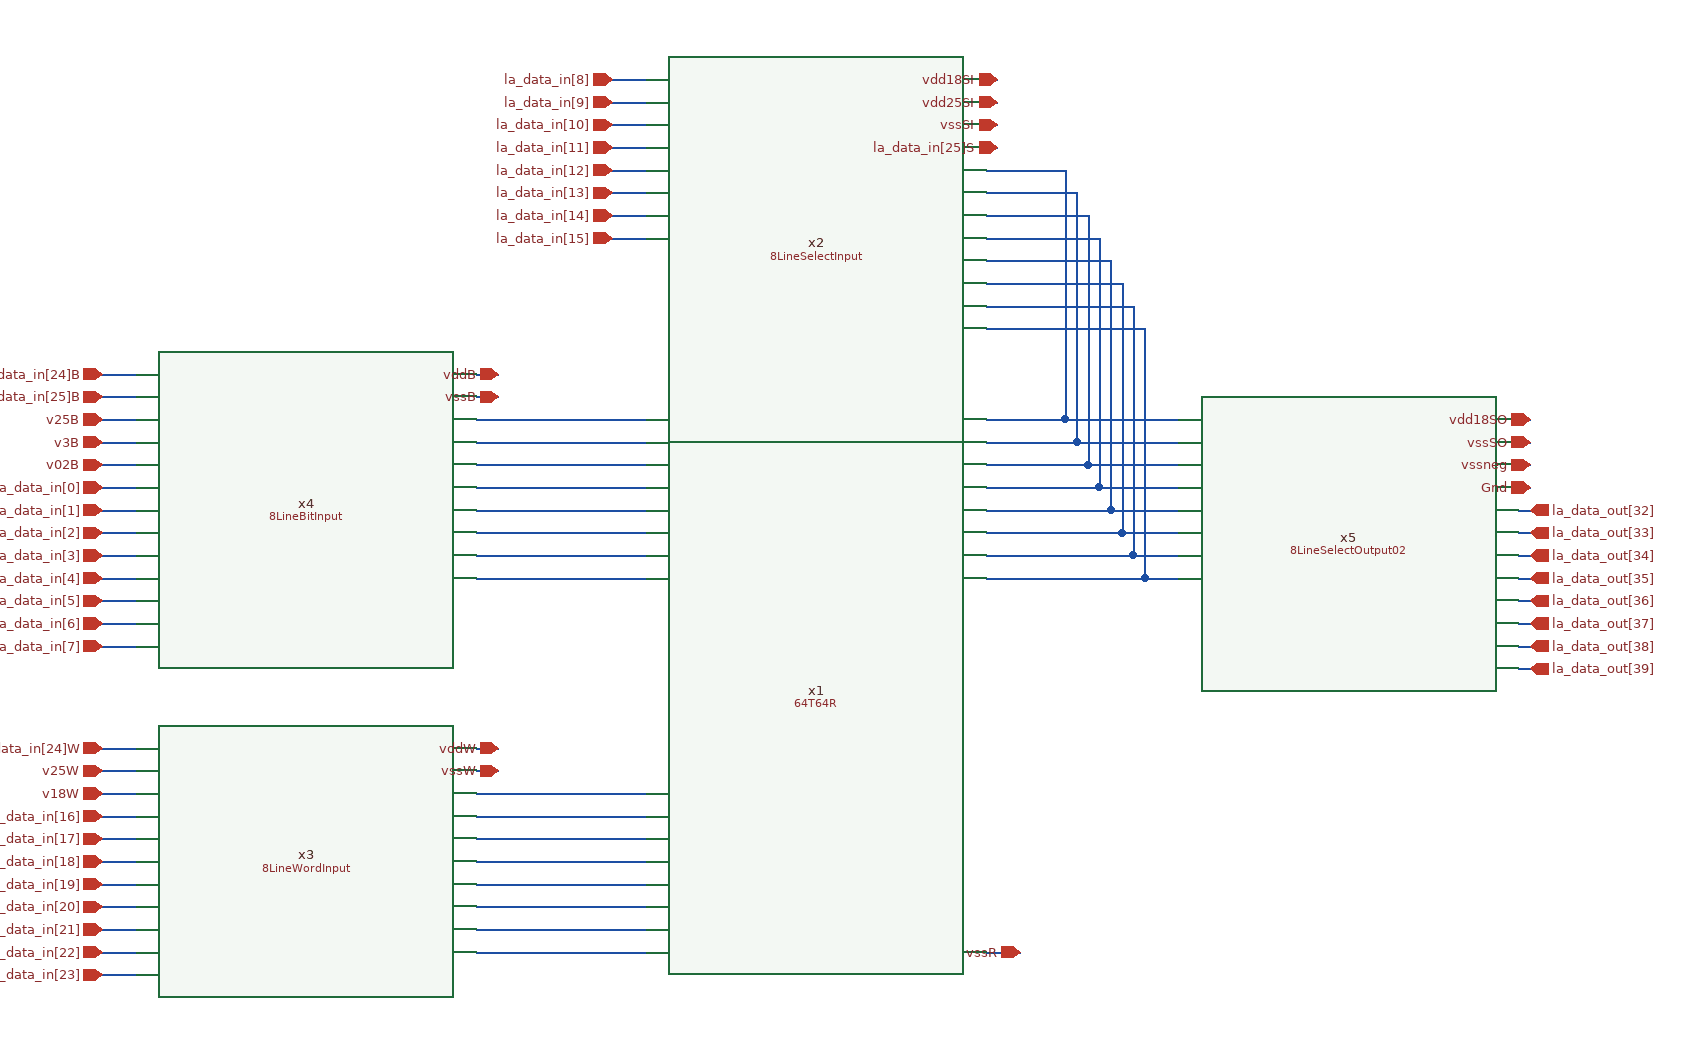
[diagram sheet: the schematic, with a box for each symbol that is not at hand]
v {xschem version=3.4.4 file_version=1.2
}
G {}
K {}
V {}
S {}
E {}
N 1830 1180 1860 1180 {
lab=vssR}
N 1830 450 1840 450 {
lab=vssSI}
N 1830 410 1840 410 {
lab=vdd18SI}
N 1830 490 1900 490 {
lab=#net1}
N 1830 710 1900 710 {
lab=#net1}
N 1830 730 1910 730 {
lab=#net2}
N 1830 510 1910 510 {
lab=#net2}
N 1830 530 1920 530 {
lab=#net3}
N 1830 750 1920 750 {
lab=#net3}
N 1830 550 1930 550 {
lab=#net4}
N 1830 770 1930 770 {
lab=#net4}
N 1830 570 1940 570 {
lab=#net5}
N 1830 790 1940 790 {
lab=#net5}
N 1830 590 1950 590 {
lab=#net6}
N 1830 810 1950 810 {
lab=#net6}
N 1830 830 1960 830 {
lab=#net7}
N 1830 610 1960 610 {
lab=#net7}
N 1830 630 1970 630 {
lab=#net8}
N 1830 850 1970 850 {
lab=#net8}
N 1500 410 1530 410 {
lab=la_data_in[8]}
N 1500 430 1530 430 {
lab=la_data_in[9]}
N 1500 450 1530 450 {
lab=la_data_in[10]}
N 1500 470 1530 470 {
lab=la_data_in[11]}
N 1500 490 1530 490 {
lab=la_data_in[12]}
N 1500 510 1530 510 {
lab=la_data_in[13]}
N 1500 530 1530 530 {
lab=la_data_in[14]}
N 1500 550 1530 550 {
lab=la_data_in[15]}
N 1380 1040 1530 1040 {
lab=#net9}
N 1380 1060 1530 1060 {
lab=#net10}
N 1380 1080 1530 1080 {
lab=#net11}
N 1380 1100 1530 1100 {
lab=#net12}
N 1380 1120 1530 1120 {
lab=#net13}
N 1380 1140 1530 1140 {
lab=#net14}
N 1380 1160 1530 1160 {
lab=#net15}
N 1380 1180 1530 1180 {
lab=#net16}
N 1380 1020 1400 1020 {
lab=vssW}
N 1050 1060 1080 1060 {
lab=la_data_in[16]}
N 1050 1080 1080 1080 {
lab=la_data_in[17]}
N 1050 1100 1080 1100 {
lab=la_data_in[18]}
N 1050 1120 1080 1120 {
lab=la_data_in[19]}
N 1050 1140 1080 1140 {
lab=la_data_in[20]}
N 1050 1160 1080 1160 {
lab=la_data_in[21]}
N 1050 1180 1080 1180 {
lab=la_data_in[22]}
N 1050 1200 1080 1200 {
lab=la_data_in[23]}
N 1380 710 1530 710 {
lab=#net17}
N 1380 730 1530 730 {
lab=#net18}
N 1380 750 1530 750 {
lab=#net19}
N 1380 770 1530 770 {
lab=#net20}
N 1380 790 1530 790 {
lab=#net21}
N 1380 810 1530 810 {
lab=#net22}
N 1380 830 1530 830 {
lab=#net23}
N 1380 850 1530 850 {
lab=#net24}
N 1380 690 1400 690 {
lab=vssB}
N 1380 670 1400 670 {
lab=vddB}
N 1380 1000 1400 1000 {
lab=vddW}
N 1050 910 1080 910 {
lab=la_data_in[7]}
N 1050 890 1080 890 {
lab=la_data_in[6]}
N 1050 870 1080 870 {
lab=la_data_in[5]}
N 1050 850 1080 850 {
lab=la_data_in[4]}
N 1050 830 1080 830 {
lab=la_data_in[3]}
N 1050 810 1080 810 {
lab=la_data_in[2]}
N 1050 790 1080 790 {
lab=la_data_in[1]}
N 1050 770 1080 770 {
lab=la_data_in[0]}
N 1050 750 1080 750 {
lab=v02B}
N 1050 730 1080 730 {
lab=v3B}
N 1050 710 1080 710 {
lab=v25B}
N 1050 1040 1080 1040 {
lab=v18W}
N 1050 1020 1080 1020 {
lab=v25W}
N 1050 1000 1080 1000 {
lab=la_data_in[24]W}
N 1050 690 1080 690 {
lab=la_data_in[25]B}
N 1050 670 1080 670 {
lab=la_data_in[24]B}
N 1830 470 1840 470 {
lab=la_data_in[25]S}
N 1830 430 1840 430 {
lab=vdd25SI}
N 1900 490 1900 710 {
lab=#net1}
N 1910 510 1910 730 {
lab=#net2}
N 1920 530 1920 750 {
lab=#net3}
N 1930 550 1930 770 {
lab=#net4}
N 1940 570 1940 790 {
lab=#net5}
N 1950 590 1950 810 {
lab=#net6}
N 1960 610 1960 830 {
lab=#net7}
N 1970 630 1970 850 {
lab=#net8}
N 1970 850 2000 850 {
lab=#net8}
N 1960 830 2000 830 {
lab=#net7}
N 1950 810 2000 810 {
lab=#net6}
N 1940 790 2000 790 {
lab=#net5}
N 1930 770 2000 770 {
lab=#net4}
N 1920 750 2000 750 {
lab=#net3}
N 1910 730 2000 730 {
lab=#net2}
N 1900 710 2000 710 {
lab=#net1}
N 2300 710 2310 710 {
lab=vdd18SO}
N 2300 730 2310 730 {
lab=vssSO}
N 2300 750 2310 750 {
lab=vssneg}
N 2300 770 2310 770 {
lab=Gnd}
N 2300 790 2310 790 {
lab=la_data_out[32]}
N 2300 810 2310 810 {
lab=la_data_out[33]}
N 2300 830 2310 830 {
lab=la_data_out[34]}
N 2300 850 2310 850 {
lab=la_data_out[35]}
N 2300 870 2310 870 {
lab=la_data_out[36]}
N 2300 890 2310 890 {
lab=la_data_out[37]}
N 2300 910 2310 910 {
lab=la_data_out[38]}
N 2300 930 2310 930 {
lab=la_data_out[32]}
C {64T64R.sym} 1680 940 0 0 {name=x1}
C {8LineSelectInput.sym} 1680 520 0 0 {name=x2}
C {8LineWordInput.sym} 1230 1100 0 0 {name=x3}
C {8LineBitInput.sym} 1230 790 0 0 {name=x4}
C {devices/ipin.sym} 1500 410 0 0 {name=p1 lab=la_data_in[8]}
C {devices/ipin.sym} 1500 550 0 0 {name=p2 lab=la_data_in[15]}
C {devices/ipin.sym} 1500 430 0 0 {name=p3 lab=la_data_in[9]}
C {devices/ipin.sym} 1500 450 0 0 {name=p4 lab=la_data_in[10]}
C {devices/ipin.sym} 1500 530 0 0 {name=p5 lab=la_data_in[14]}
C {devices/ipin.sym} 1500 510 0 0 {name=p6 lab=la_data_in[13]}
C {devices/ipin.sym} 1500 490 0 0 {name=p7 lab=la_data_in[12]}
C {devices/ipin.sym} 1500 470 0 0 {name=p8 lab=la_data_in[11]}
C {devices/ipin.sym} 1050 770 0 0 {name=p9 lab=la_data_in[0]}
C {devices/ipin.sym} 1050 790 0 0 {name=p10 lab=la_data_in[1]}
C {devices/ipin.sym} 1050 810 0 0 {name=p11 lab=la_data_in[2]}
C {devices/ipin.sym} 1050 830 0 0 {name=p12 lab=la_data_in[3]}
C {devices/ipin.sym} 1050 850 0 0 {name=p13 lab=la_data_in[4]}
C {devices/ipin.sym} 1050 870 0 0 {name=p14 lab=la_data_in[5]}
C {devices/ipin.sym} 1050 890 0 0 {name=p15 lab=la_data_in[6]}
C {devices/ipin.sym} 1050 910 0 0 {name=p16 lab=la_data_in[7]}
C {devices/ipin.sym} 1050 1060 0 0 {name=p17 lab=la_data_in[16]}
C {devices/ipin.sym} 1050 1080 0 0 {name=p18 lab=la_data_in[17]}
C {devices/ipin.sym} 1050 1100 0 0 {name=p19 lab=la_data_in[18]}
C {devices/ipin.sym} 1050 1120 0 0 {name=p20 lab=la_data_in[19]}
C {devices/ipin.sym} 1050 1140 0 0 {name=p21 lab=la_data_in[20]}
C {devices/ipin.sym} 1050 1160 0 0 {name=p22 lab=la_data_in[21]}
C {devices/ipin.sym} 1050 1180 0 0 {name=p23 lab=la_data_in[22]}
C {devices/ipin.sym} 1050 1200 0 0 {name=p24 lab=la_data_in[23]}
C {devices/ipin.sym} 1050 670 0 0 {name=p25 lab=la_data_in[24]B}
C {devices/ipin.sym} 1050 1000 0 0 {name=p26 lab=la_data_in[24]W}
C {devices/ipin.sym} 1050 690 0 0 {name=p27 lab=la_data_in[25]B}
C {devices/ipin.sym} 1840 470 2 0 {name=p28 lab=la_data_in[25]S}
C {devices/ipin.sym} 1050 710 0 0 {name=p29 lab=v25B}
C {devices/ipin.sym} 1050 730 0 0 {name=p30 lab=v3B}
C {devices/ipin.sym} 1050 750 0 0 {name=p31 lab=v02B}
C {devices/ipin.sym} 1050 1020 0 0 {name=p32 lab=v25W}
C {devices/ipin.sym} 1050 1040 0 0 {name=p33 lab=v18W}
C {devices/iopin.sym} 1400 670 0 0 {name=p34 lab=vddB}
C {devices/iopin.sym} 1400 690 0 0 {name=p35 lab=vssB}
C {devices/iopin.sym} 1400 1020 0 0 {name=p36 lab=vssW}
C {devices/iopin.sym} 1400 1000 0 0 {name=p37 lab=vddW}
C {devices/iopin.sym} 1860 1180 0 0 {name=p38 lab=vssR}
C {devices/iopin.sym} 1840 410 0 0 {name=p39 lab=vdd18SI}
C {devices/iopin.sym} 1840 430 0 0 {name=p40 lab=vdd25SI}
C {devices/iopin.sym} 1840 450 0 0 {name=p41 lab=vssSI}
C {8LineSelectOutput02.sym} 2150 820 0 0 {name=x5}
C {devices/iopin.sym} 2310 710 0 0 {name=p42 lab=vdd18SO}
C {devices/iopin.sym} 2310 730 0 0 {name=p43 lab=vssSO}
C {devices/iopin.sym} 2310 770 0 0 {name=p44 lab=Gnd}
C {devices/iopin.sym} 2310 750 0 0 {name=p45 lab=vssneg}
C {devices/opin.sym} 2310 790 0 0 {name=p46 lab=la_data_out[32]}
C {devices/opin.sym} 2310 810 0 0 {name=p47 lab=la_data_out[33]}
C {devices/opin.sym} 2310 830 0 0 {name=p48 lab=la_data_out[34]}
C {devices/opin.sym} 2310 850 0 0 {name=p49 lab=la_data_out[35]}
C {devices/opin.sym} 2310 870 0 0 {name=p50 lab=la_data_out[36]}
C {devices/opin.sym} 2310 890 0 0 {name=p51 lab=la_data_out[37]}
C {devices/opin.sym} 2310 910 0 0 {name=p52 lab=la_data_out[38]}
C {devices/opin.sym} 2310 930 0 0 {name=p53 lab=la_data_out[39]}
